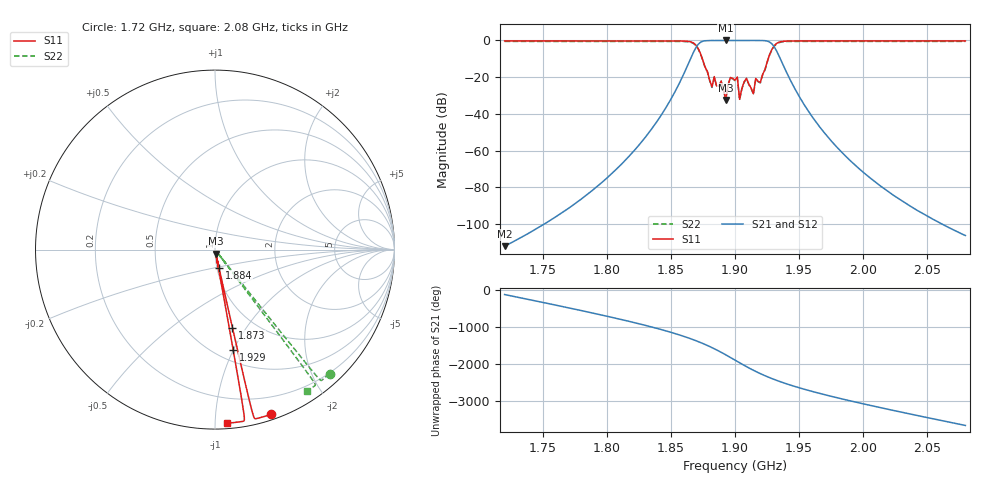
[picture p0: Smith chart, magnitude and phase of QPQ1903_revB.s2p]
! written by passband
# GHZ S DB R 50
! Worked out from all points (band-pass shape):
!   201 points, 1.72 GHz to 2.08 GHz, reference 50 ohm
!   highest |S21| = 0.00 dB at 1.893 GHz (marker M1); lowest = -112.1 dB at 1.72 GHz (marker M2)
!   |S21| within 3 dB of the highest: 1.87 GHz to 1.93 GHz (59.79 MHz wide, 3.15 % of centre)
!   lowest |S11| = -32.5 dB at 1.893 GHz (marker M3), VSWR 1.05, Z = 50.4 - j2.35 ohm
!   |S11| at or under -10 dB: 1.874 GHz to 1.926 GHz (51.43 MHz wide, 2.71 % of centre)
!   |S22| runs from -32.7 to -0.5 dB; largest |S21 - S12| = 0
!   S11 on the Smith chart (normalised r, x): 1.72 GHz: 0.05, -1.40; 1.873 GHz: 0.80, -0.87; 1.884 GHz: 1.02, -0.21; 1.929 GHz: 0.61, -1.00; 2.08 GHz: 0.03, -1.07
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1.72  -0.27 -71.1  -112.06 -130.4  -112.06 -130.4  -0.53 -47.3
1.7812  -0.27 -73.6  -85.70 147.4  -85.70 147.4  -0.53 -48.9
1.8406  -0.27 -76.1  -42.55 21.5  -42.55 21.5  -0.53 -50.6
1.8658  -0.84 -77.1  -9.12 111.1  -9.12 111.1  -1.10 -51.3
1.873  -7.03 -77.4  -1.03 15.3  -1.03 15.3  -7.29 -51.5
1.8784  -16.84 -77.6  -0.10 -64.8  -0.10 -64.8  -17.11 -51.6
1.8838  -19.69 -77.9  -0.05 -153.0  -0.05 -153.0  -19.95 -51.8
1.8892  -22.08 -78.1  -0.03 110.6  -0.03 110.6  -22.34 -51.9
1.8928  -32.47 -78.2  -0.00 42.2  -0.00 42.2  -32.74 -52.0
1.8964  -20.19 -78.4  -0.04 -28.6  -0.04 -28.6  -20.46 -52.1
1.9  -21.63 -78.5  -0.03 -100.6  -0.03 -100.6  -21.90 -52.2
1.9018  -19.93 -78.6  -0.05 -136.6  -0.05 -136.6  -20.20 -52.2
1.9036  -32.08 -78.7  -0.00 -172.5  -0.00 -172.5  -32.34 -52.3
1.9072  -22.47 -78.8  -0.03 117.0  -0.03 117.0  -22.74 -52.4
1.9126  -25.94 -79.0  -0.01 16.2  -0.01 16.2  -26.21 -52.5
1.918  -22.26 -79.3  -0.03 -76.8  -0.03 -76.8  -22.52 -52.7
1.9234  -15.85 -79.5  -0.12 -161.5  -0.12 -161.5  -16.11 -52.8
1.9288  -4.93 -79.7  -1.82 121.6  -1.82 121.6  -5.20 -53.0
1.9342  -0.99 -79.9  -8.16 51.4  -8.16 51.4  -1.25 -53.1
1.9612  -0.27 -81.1  -42.43 125.6  -42.43 125.6  -0.53 -53.9
2.0206  -0.27 -83.5  -82.77 4.0  -82.77 4.0  -0.53 -55.5
2.08  -0.27 -86.0  -106.26 -64.6  -106.26 -64.6  -0.53 -57.1
